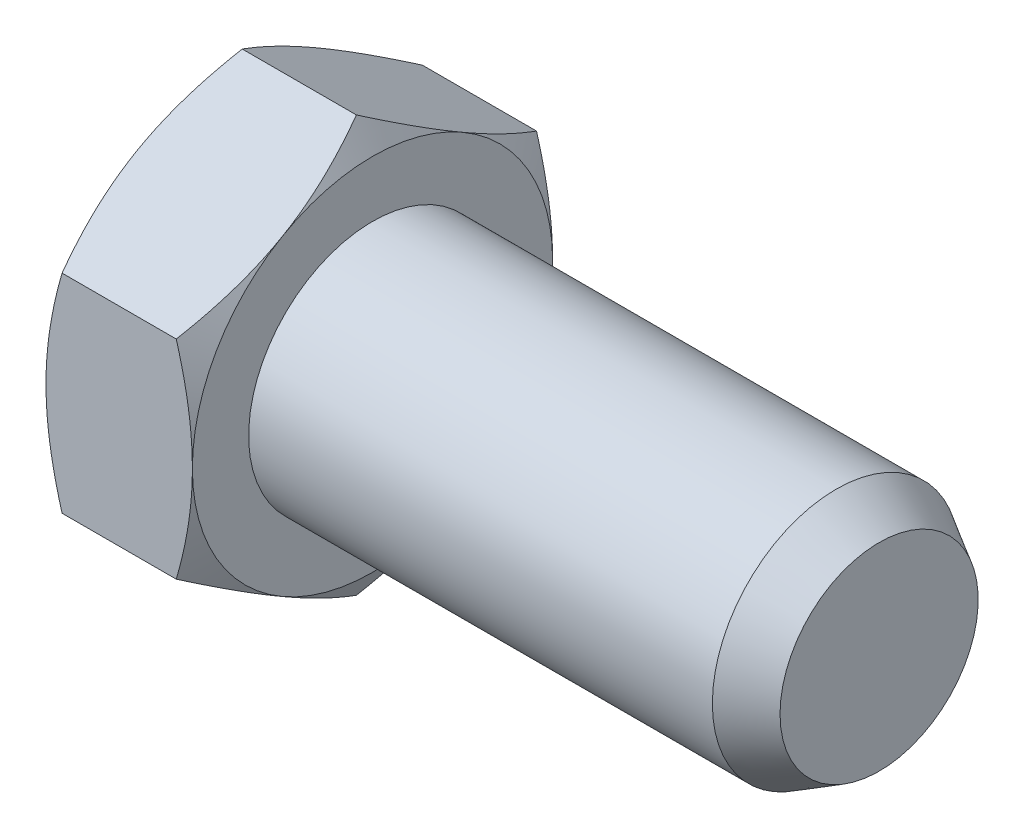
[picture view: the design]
ISO-10303-21;
HEADER;
FILE_DESCRIPTION(('STEP AP214'),'2;1');
FILE_NAME('part.step','',(''),(''),'','','');
FILE_SCHEMA(('AUTOMOTIVE_DESIGN { 1 0 10303 214 1 1 1 1 }'));
ENDSEC;
DATA;
#1=APPLICATION_CONTEXT('core data for automotive mechanical design processes');
#2=APPLICATION_PROTOCOL_DEFINITION('international standard','automotive_design',2000,#1);
#3=PRODUCT_CONTEXT('',#1,'mechanical');
#4=PRODUCT('Part','Part','',(#3));
#5=PRODUCT_RELATED_PRODUCT_CATEGORY('part','',(#4));
#6=PRODUCT_DEFINITION_FORMATION('','',#4);
#7=PRODUCT_DEFINITION_CONTEXT('part definition',#1,'design');
#8=PRODUCT_DEFINITION('design','',#6,#7);
#9=PRODUCT_DEFINITION_SHAPE('','',#8);
#10=(LENGTH_UNIT() NAMED_UNIT(*) SI_UNIT(.MILLI.,.METRE.));
#11=(NAMED_UNIT(*) PLANE_ANGLE_UNIT() SI_UNIT($,.RADIAN.));
#12=(NAMED_UNIT(*) SI_UNIT($,.STERADIAN.) SOLID_ANGLE_UNIT());
#13=UNCERTAINTY_MEASURE_WITH_UNIT(LENGTH_MEASURE(1.E-05),#10,'distance_accuracy_value','');
#14=(GEOMETRIC_REPRESENTATION_CONTEXT(3) GLOBAL_UNCERTAINTY_ASSIGNED_CONTEXT((#13)) GLOBAL_UNIT_ASSIGNED_CONTEXT((#10,
#11,#12)) REPRESENTATION_CONTEXT('',''));
#15=CARTESIAN_POINT('',(0.,0.,0.));
#16=DIRECTION('',(0.,0.,1.));
#17=DIRECTION('',(1.,0.,0.));
#18=AXIS2_PLACEMENT_3D('',#15,#16,#17);
#19=CARTESIAN_POINT('',(0.,0.,0.));
#20=DIRECTION('',(-1.,0.,0.));
#21=DIRECTION('',(0.,0.,1.));
#22=AXIS2_PLACEMENT_3D('',#19,#20,#21);
#23=PLANE('',#22);
#24=CARTESIAN_POINT('',(0.,0.,0.));
#25=DIRECTION('',(-1.,0.,0.));
#26=DIRECTION('',(0.,0.,1.));
#27=AXIS2_PLACEMENT_3D('',#24,#25,#26);
#28=CIRCLE('',#27,1.6);
#29=CARTESIAN_POINT('',(0.,0.,1.6));
#30=VERTEX_POINT('',#29);
#31=CARTESIAN_POINT('',(0.,-1.3856406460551,0.799999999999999));
#32=VERTEX_POINT('',#31);
#33=EDGE_CURVE('E167',#30,#32,#28,.F.);
#34=ORIENTED_EDGE('',*,*,#33,.F.);
#35=CARTESIAN_POINT('',(0.,1.3856406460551,0.8));
#36=VERTEX_POINT('',#35);
#37=EDGE_CURVE('E129',#36,#30,#28,.F.);
#38=ORIENTED_EDGE('',*,*,#37,.F.);
#39=CARTESIAN_POINT('',(0.,1.3856406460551,-0.799999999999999));
#40=VERTEX_POINT('',#39);
#41=EDGE_CURVE('E166',#40,#36,#28,.F.);
#42=ORIENTED_EDGE('',*,*,#41,.F.);
#43=CARTESIAN_POINT('',(0.,0.,-1.6));
#44=VERTEX_POINT('',#43);
#45=EDGE_CURVE('E298',#44,#40,#28,.F.);
#46=ORIENTED_EDGE('',*,*,#45,.F.);
#47=CARTESIAN_POINT('',(0.,-1.3856406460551,-0.8));
#48=VERTEX_POINT('',#47);
#49=EDGE_CURVE('E302',#48,#44,#28,.F.);
#50=ORIENTED_EDGE('',*,*,#49,.F.);
#51=EDGE_CURVE('E309',#32,#48,#28,.F.);
#52=ORIENTED_EDGE('',*,*,#51,.F.);
#53=EDGE_LOOP('',(#34,#38,#42,#46,#50,#52));
#54=FACE_BOUND('',#53,.T.);
#55=CARTESIAN_POINT('',(0.,0.,0.));
#56=DIRECTION('',(-1.,0.,0.));
#57=DIRECTION('',(0.,0.,1.));
#58=AXIS2_PLACEMENT_3D('',#55,#56,#57);
#59=CIRCLE('',#58,1.28);
#60=CARTESIAN_POINT('',(0.,0.,1.28));
#61=VERTEX_POINT('',#60);
#62=EDGE_CURVE('E176',#61,#61,#59,.F.);
#63=ORIENTED_EDGE('',*,*,#62,.T.);
#64=EDGE_LOOP('',(#63));
#65=FACE_BOUND('',#64,.T.);
#66=ADVANCED_FACE('F33',(#54,#65),#23,.T.);
#67=CARTESIAN_POINT('',(1.3,1.4,0.));
#68=DIRECTION('',(1.,0.,0.));
#69=DIRECTION('',(0.,0.,-1.));
#70=AXIS2_PLACEMENT_3D('',#67,#68,#69);
#71=PLANE('',#70);
#72=CARTESIAN_POINT('',(1.3,0.,0.));
#73=DIRECTION('',(1.,0.,0.));
#74=DIRECTION('',(0.,0.,-1.));
#75=AXIS2_PLACEMENT_3D('',#72,#73,#74);
#76=CIRCLE('',#75,1.6);
#77=CARTESIAN_POINT('',(1.3,-1.3856406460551,-0.8));
#78=VERTEX_POINT('',#77);
#79=CARTESIAN_POINT('',(1.3,0.,-1.6));
#80=VERTEX_POINT('',#79);
#81=EDGE_CURVE('E48',#78,#80,#76,.T.);
#82=ORIENTED_EDGE('',*,*,#81,.T.);
#83=CARTESIAN_POINT('',(1.3,1.3856406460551,-0.799999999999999));
#84=VERTEX_POINT('',#83);
#85=EDGE_CURVE('E56',#80,#84,#76,.T.);
#86=ORIENTED_EDGE('',*,*,#85,.T.);
#87=CARTESIAN_POINT('',(1.3,1.3856406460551,0.800000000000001));
#88=VERTEX_POINT('',#87);
#89=EDGE_CURVE('E345',#84,#88,#76,.T.);
#90=ORIENTED_EDGE('',*,*,#89,.T.);
#91=CARTESIAN_POINT('',(1.3,0.,1.6));
#92=VERTEX_POINT('',#91);
#93=EDGE_CURVE('E343',#88,#92,#76,.T.);
#94=ORIENTED_EDGE('',*,*,#93,.T.);
#95=CARTESIAN_POINT('',(1.3,-1.3856406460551,0.799999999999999));
#96=VERTEX_POINT('',#95);
#97=EDGE_CURVE('E339',#92,#96,#76,.T.);
#98=ORIENTED_EDGE('',*,*,#97,.T.);
#99=EDGE_CURVE('E332',#96,#78,#76,.T.);
#100=ORIENTED_EDGE('',*,*,#99,.T.);
#101=EDGE_LOOP('',(#82,#86,#90,#94,#98,#100));
#102=FACE_BOUND('',#101,.T.);
#103=CARTESIAN_POINT('',(1.3,0.,0.));
#104=DIRECTION('',(1.,0.,0.));
#105=DIRECTION('',(0.,0.,-1.));
#106=AXIS2_PLACEMENT_3D('',#103,#104,#105);
#107=CIRCLE('',#106,1.1);
#108=CARTESIAN_POINT('',(1.3,0.,-1.1));
#109=VERTEX_POINT('',#108);
#110=EDGE_CURVE('E161',#109,#109,#107,.T.);
#111=ORIENTED_EDGE('',*,*,#110,.F.);
#112=EDGE_LOOP('',(#111));
#113=FACE_BOUND('',#112,.T.);
#114=ADVANCED_FACE('F340',(#102,#113),#71,.T.);
#115=CARTESIAN_POINT('',(13.1078858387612,0.,0.));
#116=DIRECTION('',(1.,0.,0.));
#117=DIRECTION('',(0.,0.,-1.));
#118=AXIS2_PLACEMENT_3D('',#115,#116,#117);
#119=CYLINDRICAL_SURFACE('',#118,1.1);
#120=CARTESIAN_POINT('',(5.41894882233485,0.,0.));
#121=DIRECTION('',(1.,0.,0.));
#122=DIRECTION('',(0.,0.,-1.));
#123=AXIS2_PLACEMENT_3D('',#120,#121,#122);
#124=CIRCLE('',#123,1.1);
#125=CARTESIAN_POINT('',(5.41894882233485,0.,1.1));
#126=VERTEX_POINT('',#125);
#127=EDGE_CURVE('E11',#126,#126,#124,.F.);
#128=ORIENTED_EDGE('',*,*,#127,.T.);
#129=EDGE_LOOP('',(#128));
#130=FACE_BOUND('',#129,.T.);
#131=ORIENTED_EDGE('',*,*,#110,.T.);
#132=EDGE_LOOP('',(#131));
#133=FACE_BOUND('',#132,.T.);
#134=ADVANCED_FACE('F370',(#130,#133),#119,.T.);
#135=CARTESIAN_POINT('',(5.8,1.1,0.));
#136=DIRECTION('',(1.,0.,0.));
#137=DIRECTION('',(0.,0.,-1.));
#138=AXIS2_PLACEMENT_3D('',#135,#136,#137);
#139=PLANE('',#138);
#140=CARTESIAN_POINT('',(5.8,0.,0.));
#141=DIRECTION('',(1.,0.,0.));
#142=DIRECTION('',(0.,0.,-1.));
#143=AXIS2_PLACEMENT_3D('',#140,#141,#142);
#144=CIRCLE('',#143,0.879999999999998);
#145=CARTESIAN_POINT('',(5.8,0.,0.879999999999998));
#146=VERTEX_POINT('',#145);
#147=EDGE_CURVE('E41',#146,#146,#144,.T.);
#148=ORIENTED_EDGE('',*,*,#147,.T.);
#149=EDGE_LOOP('',(#148));
#150=FACE_BOUND('',#149,.T.);
#151=ADVANCED_FACE('F356',(#150),#139,.T.);
#152=CARTESIAN_POINT('',(0.65,0.,0.));
#153=DIRECTION('',(-1.,0.,0.));
#154=DIRECTION('',(0.,0.,1.));
#155=AXIS2_PLACEMENT_3D('',#152,#153,#154);
#156=CONICAL_SURFACE('',#155,2.72583302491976,1.04719755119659);
#157=CARTESIAN_POINT('',(1.15702709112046,-0.923644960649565,1.6002));
#158=CARTESIAN_POINT('',(1.18047613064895,-0.964240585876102,1.52988631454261));
#159=CARTESIAN_POINT('',(1.20180264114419,-1.00518662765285,1.45896568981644));
#160=CARTESIAN_POINT('',(1.23902934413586,-1.08778782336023,1.31589622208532));
#161=CARTESIAN_POINT('',(1.25491636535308,-1.12944444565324,1.24374483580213));
#162=CARTESIAN_POINT('',(1.27964828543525,-1.21224140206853,1.10033630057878));
#163=CARTESIAN_POINT('',(1.28865776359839,-1.25336899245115,1.02910122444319));
#164=CARTESIAN_POINT('',(1.299415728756,-1.33581782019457,0.886295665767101));
#165=CARTESIAN_POINT('',(1.30117312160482,-1.37713875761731,0.814725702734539));
#166=CARTESIAN_POINT('',(1.29752882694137,-1.45435771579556,0.680978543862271));
#167=CARTESIAN_POINT('',(1.29302194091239,-1.49026726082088,0.618781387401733));
#168=CARTESIAN_POINT('',(1.27873412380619,-1.5618523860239,0.494792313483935));
#169=CARTESIAN_POINT('',(1.26894830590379,-1.59752771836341,0.433000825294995));
#170=CARTESIAN_POINT('',(1.24448308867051,-1.66926059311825,0.30875584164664));
#171=CARTESIAN_POINT('',(1.22969992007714,-1.70530905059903,0.246318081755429));
#172=CARTESIAN_POINT('',(1.19614739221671,-1.77686812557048,0.122374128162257));
#173=CARTESIAN_POINT('',(1.17738592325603,-1.81237966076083,0.0608663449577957));
#174=CARTESIAN_POINT('',(1.15702709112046,-1.84763633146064,-0.000199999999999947));
#175=B_SPLINE_CURVE_WITH_KNOTS('',3,(#157,#158,#159,#160,#161,#162,#163,#164,#165,#166,#167,
#168,#169,#170,#171,#172,#173,#174),.UNSPECIFIED.,.F.,.F.,(4,2,2,2,2,2,2,2,4),(0.,
0.253628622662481,0.507867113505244,0.755812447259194,1.0034532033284,1.21912891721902,
1.43500463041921,1.65567058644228,1.87590291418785),.UNSPECIFIED.);
#176=CARTESIAN_POINT('',(1.15709376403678,-0.923760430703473,1.6));
#177=VERTEX_POINT('',#176);
#178=EDGE_CURVE('E157',#177,#96,#175,.T.);
#179=ORIENTED_EDGE('',*,*,#178,.T.);
#180=ORIENTED_EDGE('',*,*,#97,.F.);
#181=CARTESIAN_POINT('',(0.499873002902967,-2.52098464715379,1.6));
#182=CARTESIAN_POINT('',(0.534095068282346,-2.45076148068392,1.6));
#183=CARTESIAN_POINT('',(0.568000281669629,-2.38038131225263,1.6));
#184=CARTESIAN_POINT('',(0.634999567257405,-2.23922362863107,1.6));
#185=CARTESIAN_POINT('',(0.668093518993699,-2.16844605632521,1.6));
#186=CARTESIAN_POINT('',(0.733450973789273,-2.02606417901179,1.6));
#187=CARTESIAN_POINT('',(0.765709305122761,-1.95445749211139,1.6));
#188=CARTESIAN_POINT('',(0.828957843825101,-1.8106883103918,1.6));
#189=CARTESIAN_POINT('',(0.859948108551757,-1.73852584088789,1.6));
#190=CARTESIAN_POINT('',(0.921362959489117,-1.59104276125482,1.6));
#191=CARTESIAN_POINT('',(0.951731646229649,-1.51569874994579,1.6));
#192=CARTESIAN_POINT('',(1.01025914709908,-1.36415873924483,1.6));
#193=CARTESIAN_POINT('',(1.03841815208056,-1.28796281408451,1.6));
#194=CARTESIAN_POINT('',(1.09182525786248,-1.13470603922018,1.6));
#195=CARTESIAN_POINT('',(1.11707865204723,-1.05764705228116,1.6));
#196=CARTESIAN_POINT('',(1.16388736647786,-0.90242428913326,1.6));
#197=CARTESIAN_POINT('',(1.18544381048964,-0.824260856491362,1.6));
#198=CARTESIAN_POINT('',(1.22373292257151,-0.667228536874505,1.6));
#199=CARTESIAN_POINT('',(1.24049328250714,-0.588366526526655,1.6));
#200=CARTESIAN_POINT('',(1.26827361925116,-0.429622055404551,1.6));
#201=CARTESIAN_POINT('',(1.27929420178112,-0.349739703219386,1.6));
#202=CARTESIAN_POINT('',(1.2945707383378,-0.190409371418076,1.6));
#203=CARTESIAN_POINT('',(1.29891670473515,-0.110970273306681,1.6));
#204=CARTESIAN_POINT('',(1.30072544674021,0.0479847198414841,1.6));
#205=CARTESIAN_POINT('',(1.29818818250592,0.127500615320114,1.6));
#206=CARTESIAN_POINT('',(1.28423345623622,0.315948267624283,1.6));
#207=CARTESIAN_POINT('',(1.2698270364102,0.42466064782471,1.6));
#208=CARTESIAN_POINT('',(1.23056818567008,0.640184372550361,1.6));
#209=CARTESIAN_POINT('',(1.20570615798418,0.746993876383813,1.6));
#210=CARTESIAN_POINT('',(1.14763012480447,0.960879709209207,1.6));
#211=CARTESIAN_POINT('',(1.11423830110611,1.06790639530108,1.6));
#212=CARTESIAN_POINT('',(1.04181251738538,1.2799660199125,1.6));
#213=CARTESIAN_POINT('',(1.0027798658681,1.38499941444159,1.6));
#214=CARTESIAN_POINT('',(0.930792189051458,1.56799469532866,1.6));
#215=CARTESIAN_POINT('',(0.898685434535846,1.64629502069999,1.6));
#216=CARTESIAN_POINT('',(0.832721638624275,1.80215714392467,1.6));
#217=CARTESIAN_POINT('',(0.798864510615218,1.8797189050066,1.6));
#218=CARTESIAN_POINT('',(0.695256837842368,2.11154275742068,1.6));
#219=CARTESIAN_POINT('',(0.623487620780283,2.26490000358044,1.6));
#220=CARTESIAN_POINT('',(0.476501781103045,2.57016984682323,1.6));
#221=CARTESIAN_POINT('',(0.401280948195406,2.72208039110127,1.6));
#222=CARTESIAN_POINT('',(0.248594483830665,3.02477374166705,1.6));
#223=CARTESIAN_POINT('',(0.171128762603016,3.17555650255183,1.6));
#224=CARTESIAN_POINT('',(0.021984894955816,3.46221292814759,1.6));
#225=CARTESIAN_POINT('',(-0.0495548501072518,3.59815887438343,1.6));
#226=CARTESIAN_POINT('',(-0.1935806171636,3.86955633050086,1.6));
#227=CARTESIAN_POINT('',(-0.266066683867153,4.00500781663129,1.6));
#228=CARTESIAN_POINT('',(-0.411533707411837,4.27512524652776,1.6));
#229=CARTESIAN_POINT('',(-0.484512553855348,4.40979232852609,1.6));
#230=CARTESIAN_POINT('',(-0.631022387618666,4.67881425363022,1.6));
#231=CARTESIAN_POINT('',(-0.704553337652,4.81316911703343,1.6));
#232=CARTESIAN_POINT('',(-0.778287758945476,4.94741144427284,1.6));
#233=B_SPLINE_CURVE_WITH_KNOTS('',3,(#181,#182,#183,#184,#185,#186,#187,#188,#189,#190,#191,
#192,#193,#194,#195,#196,#197,#198,#199,#200,#201,#202,#203,#204,#205,#206,#207,#208,#209,#210,
#211,#212,#213,#214,#215,#216,#217,#218,#219,#220,#221,#222,#223,#224,#225,#226,#227,#228,#229,
#230,#231,#232),.UNSPECIFIED.,.F.,.F.,(4,2,2,2,2,2,2,2,2,2,2,2,2,2,2,2,2,2,2,2,2,2,2,2,2,4),(0.,
0.234357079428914,0.468748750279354,0.704350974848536,0.939942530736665,1.18361811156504,
1.42727262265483,1.67047597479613,1.91360526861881,2.15530105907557,2.39697133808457,
2.63535296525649,2.87373597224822,3.20204898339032,3.53066399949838,3.86678588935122,
4.2028299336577,4.45668877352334,4.71056018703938,5.21844347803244,5.72696367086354,
6.23550422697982,6.69636122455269,7.15724007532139,7.61674952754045,8.0762282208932),.UNSPECIFIED.);
#234=EDGE_CURVE('E168',#92,#177,#233,.F.);
#235=ORIENTED_EDGE('',*,*,#234,.T.);
#236=EDGE_LOOP('',(#179,#180,#235));
#237=FACE_BOUND('',#236,.T.);
#238=ADVANCED_FACE('F376',(#237),#156,.T.);
#239=CARTESIAN_POINT('',(1.15702709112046,1.84763633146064,-0.0001999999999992));
#240=CARTESIAN_POINT('',(1.18047613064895,1.8070407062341,0.0701136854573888));
#241=CARTESIAN_POINT('',(1.20180264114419,1.76609466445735,0.14103431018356));
#242=CARTESIAN_POINT('',(1.23902934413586,1.68349346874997,0.284103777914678));
#243=CARTESIAN_POINT('',(1.25491636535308,1.64183684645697,0.356255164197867));
#244=CARTESIAN_POINT('',(1.27964828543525,1.55903989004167,0.499663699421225));
#245=CARTESIAN_POINT('',(1.28865776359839,1.51791229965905,0.570898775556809));
#246=CARTESIAN_POINT('',(1.299415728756,1.43546347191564,0.713704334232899));
#247=CARTESIAN_POINT('',(1.30117312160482,1.39414253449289,0.785274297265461));
#248=CARTESIAN_POINT('',(1.29752882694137,1.31692357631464,0.919021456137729));
#249=CARTESIAN_POINT('',(1.29302194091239,1.28101403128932,0.981218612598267));
#250=CARTESIAN_POINT('',(1.27873412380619,1.20942890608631,1.10520768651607));
#251=CARTESIAN_POINT('',(1.26894830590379,1.1737535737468,1.16699917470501));
#252=CARTESIAN_POINT('',(1.24448308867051,1.10202069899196,1.29124415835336));
#253=CARTESIAN_POINT('',(1.22969992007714,1.06597224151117,1.35368191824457));
#254=CARTESIAN_POINT('',(1.19614739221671,0.994413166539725,1.47762587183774));
#255=CARTESIAN_POINT('',(1.17738592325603,0.958901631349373,1.5391336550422));
#256=CARTESIAN_POINT('',(1.15702709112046,0.923644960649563,1.6002));
#257=B_SPLINE_CURVE_WITH_KNOTS('',3,(#239,#240,#241,#242,#243,#244,#245,#246,#247,#248,#249,
#250,#251,#252,#253,#254,#255,#256),.UNSPECIFIED.,.F.,.F.,(4,2,2,2,2,2,2,2,4),(0.,
0.253628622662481,0.507867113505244,0.755812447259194,1.0034532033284,1.21912891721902,
1.43500463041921,1.65567058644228,1.87590291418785),.UNSPECIFIED.);
#258=CARTESIAN_POINT('',(1.15709376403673,0.923760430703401,1.6));
#259=VERTEX_POINT('',#258);
#260=EDGE_CURVE('E317',#88,#259,#257,.T.);
#261=ORIENTED_EDGE('',*,*,#260,.T.);
#262=EDGE_CURVE('E150',#259,#92,#233,.F.);
#263=ORIENTED_EDGE('',*,*,#262,.T.);
#264=ORIENTED_EDGE('',*,*,#93,.F.);
#265=EDGE_LOOP('',(#261,#263,#264));
#266=FACE_BOUND('',#265,.T.);
#267=ADVANCED_FACE('F177',(#266),#156,.T.);
#268=CARTESIAN_POINT('',(1.15702709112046,0.923644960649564,-1.6002));
#269=CARTESIAN_POINT('',(1.18047613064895,0.964240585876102,-1.52988631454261));
#270=CARTESIAN_POINT('',(1.20180264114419,1.00518662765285,-1.45896568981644));
#271=CARTESIAN_POINT('',(1.23902934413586,1.08778782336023,-1.31589622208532));
#272=CARTESIAN_POINT('',(1.25491636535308,1.12944444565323,-1.24374483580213));
#273=CARTESIAN_POINT('',(1.27964828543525,1.21224140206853,-1.10033630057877));
#274=CARTESIAN_POINT('',(1.28865776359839,1.25336899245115,-1.02910122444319));
#275=CARTESIAN_POINT('',(1.299415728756,1.33581782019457,-0.886295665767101));
#276=CARTESIAN_POINT('',(1.30117312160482,1.37713875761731,-0.814725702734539));
#277=CARTESIAN_POINT('',(1.29752882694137,1.45435771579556,-0.680978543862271));
#278=CARTESIAN_POINT('',(1.29302194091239,1.49026726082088,-0.618781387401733));
#279=CARTESIAN_POINT('',(1.27873412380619,1.5618523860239,-0.494792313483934));
#280=CARTESIAN_POINT('',(1.26894830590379,1.59752771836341,-0.433000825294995));
#281=CARTESIAN_POINT('',(1.24448308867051,1.66926059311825,-0.30875584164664));
#282=CARTESIAN_POINT('',(1.22969992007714,1.70530905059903,-0.246318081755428));
#283=CARTESIAN_POINT('',(1.19614739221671,1.77686812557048,-0.122374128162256));
#284=CARTESIAN_POINT('',(1.17738592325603,1.81237966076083,-0.0608663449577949));
#285=CARTESIAN_POINT('',(1.15702709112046,1.84763633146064,0.000200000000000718));
#286=B_SPLINE_CURVE_WITH_KNOTS('',3,(#268,#269,#270,#271,#272,#273,#274,#275,#276,#277,#278,
#279,#280,#281,#282,#283,#284,#285),.UNSPECIFIED.,.F.,.F.,(4,2,2,2,2,2,2,2,4),(0.,
0.253628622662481,0.507867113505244,0.755812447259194,1.0034532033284,1.21912891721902,
1.43500463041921,1.65567058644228,1.87590291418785),.UNSPECIFIED.);
#287=CARTESIAN_POINT('',(1.15709376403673,1.8475208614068,0.));
#288=VERTEX_POINT('',#287);
#289=EDGE_CURVE('E261',#84,#288,#286,.T.);
#290=ORIENTED_EDGE('',*,*,#289,.T.);
#291=EDGE_CURVE('E321',#288,#88,#257,.T.);
#292=ORIENTED_EDGE('',*,*,#291,.T.);
#293=ORIENTED_EDGE('',*,*,#89,.F.);
#294=EDGE_LOOP('',(#290,#292,#293));
#295=FACE_BOUND('',#294,.T.);
#296=ADVANCED_FACE('F351',(#295),#156,.T.);
#297=CARTESIAN_POINT('',(0.499873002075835,-2.5209846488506,-1.6));
#298=CARTESIAN_POINT('',(0.53409506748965,-2.45076148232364,-1.6));
#299=CARTESIAN_POINT('',(0.568000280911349,-2.38038131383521,-1.6));
#300=CARTESIAN_POINT('',(0.634999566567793,-2.23922363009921,-1.6));
#301=CARTESIAN_POINT('',(0.668093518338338,-2.16844605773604,-1.6));
#302=CARTESIAN_POINT('',(0.733450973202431,-2.02606418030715,-1.6));
#303=CARTESIAN_POINT('',(0.765709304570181,-1.95445749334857,-1.6));
#304=CARTESIAN_POINT('',(0.828957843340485,-1.81068831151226,-1.6));
#305=CARTESIAN_POINT('',(0.859948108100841,-1.73852584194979,-1.6));
#306=CARTESIAN_POINT('',(0.921362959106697,-1.59104276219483,-1.6));
#307=CARTESIAN_POINT('',(0.951731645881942,-1.51569875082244,-1.6));
#308=CARTESIAN_POINT('',(1.01025914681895,-1.36415873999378,-1.6));
#309=CARTESIAN_POINT('',(1.0384181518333,-1.28796281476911,-1.6));
#310=CARTESIAN_POINT('',(1.09182525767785,-1.1347060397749,-1.6));
#311=CARTESIAN_POINT('',(1.11707865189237,-1.05764705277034,-1.6));
#312=CARTESIAN_POINT('',(1.16388736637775,-0.902424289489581,-1.6));
#313=CARTESIAN_POINT('',(1.1854438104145,-0.824260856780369,-1.6));
#314=CARTESIAN_POINT('',(1.22373292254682,-0.667228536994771,-1.6));
#315=CARTESIAN_POINT('',(1.24049328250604,-0.588366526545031,-1.6));
#316=CARTESIAN_POINT('',(1.26827361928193,-0.429622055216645,-1.6));
#317=CARTESIAN_POINT('',(1.27929420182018,-0.349739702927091,-1.6));
#318=CARTESIAN_POINT('',(1.29457073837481,-0.190409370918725,-1.6));
#319=CARTESIAN_POINT('',(1.29891670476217,-0.110970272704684,-1.6));
#320=CARTESIAN_POINT('',(1.30072544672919,0.0479847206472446,-1.6));
#321=CARTESIAN_POINT('',(1.29818818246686,0.127500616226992,-1.6));
#322=CARTESIAN_POINT('',(1.28423345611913,0.315948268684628,-1.6));
#323=CARTESIAN_POINT('',(1.26982703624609,0.424660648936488,-1.6));
#324=CARTESIAN_POINT('',(1.23056818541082,0.640184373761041,-1.6));
#325=CARTESIAN_POINT('',(1.20570615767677,0.746993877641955,-1.6));
#326=CARTESIAN_POINT('',(1.14763012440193,0.960879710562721,-1.6));
#327=CARTESIAN_POINT('',(1.11423830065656,1.06790639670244,-1.6));
#328=CARTESIAN_POINT('',(1.0418125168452,1.27996602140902,-1.6));
#329=CARTESIAN_POINT('',(1.0027798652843,1.38499941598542,-1.6));
#330=CARTESIAN_POINT('',(0.930792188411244,1.56799469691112,-1.6));
#331=CARTESIAN_POINT('',(0.898685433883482,1.64629502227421,-1.6));
#332=CARTESIAN_POINT('',(0.832721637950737,1.80215714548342,-1.6));
#333=CARTESIAN_POINT('',(0.798864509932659,1.87971890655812,-1.6));
#334=CARTESIAN_POINT('',(0.695256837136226,2.11154275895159,-1.6));
#335=CARTESIAN_POINT('',(0.623487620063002,2.26490000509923,-1.6));
#336=CARTESIAN_POINT('',(0.476501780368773,2.57016984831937,-1.6));
#337=CARTESIAN_POINT('',(0.401280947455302,2.7220803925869,-1.6));
#338=CARTESIAN_POINT('',(0.248594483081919,3.02477374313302,-1.6));
#339=CARTESIAN_POINT('',(0.171128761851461,3.17555650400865,-1.6));
#340=CARTESIAN_POINT('',(0.0219848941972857,3.46221292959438,-1.6));
#341=CARTESIAN_POINT('',(-0.0495548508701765,3.59815887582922,-1.6));
#342=CARTESIAN_POINT('',(-0.193580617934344,3.86955633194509,-1.6));
#343=CARTESIAN_POINT('',(-0.266066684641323,4.00500781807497,-1.6));
#344=CARTESIAN_POINT('',(-0.411533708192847,4.2751252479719,-1.6));
#345=CARTESIAN_POINT('',(-0.48451255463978,4.40979232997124,-1.6));
#346=CARTESIAN_POINT('',(-0.631022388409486,4.67881425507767,-1.6));
#347=CARTESIAN_POINT('',(-0.704553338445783,4.81316911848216,-1.6));
#348=CARTESIAN_POINT('',(-0.778287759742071,4.94741144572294,-1.6));
#349=B_SPLINE_CURVE_WITH_KNOTS('',3,(#297,#298,#299,#300,#301,#302,#303,#304,#305,#306,#307,
#308,#309,#310,#311,#312,#313,#314,#315,#316,#317,#318,#319,#320,#321,#322,#323,#324,#325,#326,
#327,#328,#329,#330,#331,#332,#333,#334,#335,#336,#337,#338,#339,#340,#341,#342,#343,#344,#345,
#346,#347,#348),.UNSPECIFIED.,.F.,.F.,(4,2,2,2,2,2,2,2,2,2,2,2,2,2,2,2,2,2,2,2,2,2,2,2,2,4),(0.,
0.234357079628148,0.468748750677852,0.704350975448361,0.939942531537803,1.1836181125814,
1.42727262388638,1.67047597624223,1.9136052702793,2.1553010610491,2.3969713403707,
2.63535296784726,2.87373597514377,3.20204898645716,3.53066400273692,3.86678589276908,
4.20282993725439,4.45668877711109,4.71056019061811,5.21844348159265,5.7269636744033,
6.23550423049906,6.69636122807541,7.15724007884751,7.61674953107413,8.07622822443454),.UNSPECIFIED.);
#350=CARTESIAN_POINT('',(1.15709376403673,0.923760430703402,-1.6));
#351=VERTEX_POINT('',#350);
#352=EDGE_CURVE('E252',#80,#351,#349,.T.);
#353=ORIENTED_EDGE('',*,*,#352,.T.);
#354=EDGE_CURVE('E260',#351,#84,#286,.T.);
#355=ORIENTED_EDGE('',*,*,#354,.T.);
#356=ORIENTED_EDGE('',*,*,#85,.F.);
#357=EDGE_LOOP('',(#353,#355,#356));
#358=FACE_BOUND('',#357,.T.);
#359=ADVANCED_FACE('F388',(#358),#156,.T.);
#360=CARTESIAN_POINT('',(1.15702709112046,-1.84763633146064,0.0002));
#361=CARTESIAN_POINT('',(1.18047613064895,-1.8070407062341,-0.0701136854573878));
#362=CARTESIAN_POINT('',(1.20180264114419,-1.76609466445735,-0.141034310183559));
#363=CARTESIAN_POINT('',(1.23902934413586,-1.68349346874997,-0.284103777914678));
#364=CARTESIAN_POINT('',(1.25491636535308,-1.64183684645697,-0.356255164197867));
#365=CARTESIAN_POINT('',(1.27964828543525,-1.55903989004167,-0.499663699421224));
#366=CARTESIAN_POINT('',(1.28865776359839,-1.51791229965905,-0.570898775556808));
#367=CARTESIAN_POINT('',(1.299415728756,-1.43546347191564,-0.713704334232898));
#368=CARTESIAN_POINT('',(1.30117312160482,-1.39414253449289,-0.78527429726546));
#369=CARTESIAN_POINT('',(1.29752882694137,-1.31692357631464,-0.919021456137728));
#370=CARTESIAN_POINT('',(1.29302194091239,-1.28101403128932,-0.981218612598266));
#371=CARTESIAN_POINT('',(1.27873412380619,-1.20942890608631,-1.10520768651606));
#372=CARTESIAN_POINT('',(1.26894830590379,-1.1737535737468,-1.166999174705));
#373=CARTESIAN_POINT('',(1.24448308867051,-1.10202069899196,-1.29124415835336));
#374=CARTESIAN_POINT('',(1.22969992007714,-1.06597224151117,-1.35368191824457));
#375=CARTESIAN_POINT('',(1.19614739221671,-0.994413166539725,-1.47762587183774));
#376=CARTESIAN_POINT('',(1.17738592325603,-0.958901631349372,-1.5391336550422));
#377=CARTESIAN_POINT('',(1.15702709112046,-0.923644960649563,-1.6002));
#378=B_SPLINE_CURVE_WITH_KNOTS('',3,(#360,#361,#362,#363,#364,#365,#366,#367,#368,#369,#370,
#371,#372,#373,#374,#375,#376,#377),.UNSPECIFIED.,.F.,.F.,(4,2,2,2,2,2,2,2,4),(0.,
0.253628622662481,0.507867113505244,0.755812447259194,1.0034532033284,1.21912891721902,
1.43500463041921,1.65567058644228,1.87590291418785),.UNSPECIFIED.);
#379=CARTESIAN_POINT('',(1.15709376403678,-0.923760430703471,-1.6));
#380=VERTEX_POINT('',#379);
#381=EDGE_CURVE('E266',#78,#380,#378,.T.);
#382=ORIENTED_EDGE('',*,*,#381,.T.);
#383=EDGE_CURVE('E259',#380,#80,#349,.T.);
#384=ORIENTED_EDGE('',*,*,#383,.T.);
#385=ORIENTED_EDGE('',*,*,#81,.F.);
#386=EDGE_LOOP('',(#382,#384,#385));
#387=FACE_BOUND('',#386,.T.);
#388=ADVANCED_FACE('F384',(#387),#156,.T.);
#389=CARTESIAN_POINT('',(1.15709376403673,-1.8475208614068,0.));
#390=VERTEX_POINT('',#389);
#391=EDGE_CURVE('E273',#96,#390,#175,.T.);
#392=ORIENTED_EDGE('',*,*,#391,.T.);
#393=EDGE_CURVE('E272',#390,#78,#378,.T.);
#394=ORIENTED_EDGE('',*,*,#393,.T.);
#395=ORIENTED_EDGE('',*,*,#99,.F.);
#396=EDGE_LOOP('',(#392,#394,#395));
#397=FACE_BOUND('',#396,.T.);
#398=ADVANCED_FACE('F185',(#397),#156,.T.);
#399=CARTESIAN_POINT('',(1.3,-0.923760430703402,1.6));
#400=DIRECTION('',(0.,0.,1.));
#401=DIRECTION('',(0.,-1.,0.));
#402=AXIS2_PLACEMENT_3D('',#399,#400,#401);
#403=PLANE('',#402);
#404=ORIENTED_EDGE('',*,*,#262,.F.);
#405=DIRECTION('',(-1.,0.,0.));
#406=VECTOR('',#405,1.);
#407=CARTESIAN_POINT('',(1.3,0.923760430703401,1.6));
#408=LINE('',#407,#406);
#409=CARTESIAN_POINT('',(0.142906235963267,0.923760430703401,1.6));
#410=VERTEX_POINT('',#409);
#411=EDGE_CURVE('E142',#259,#410,#408,.T.);
#412=ORIENTED_EDGE('',*,*,#411,.T.);
#413=CARTESIAN_POINT('',(0.800126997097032,-2.52098464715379,1.6));
#414=CARTESIAN_POINT('',(0.765904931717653,-2.45076148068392,1.6));
#415=CARTESIAN_POINT('',(0.73199971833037,-2.38038131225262,1.6));
#416=CARTESIAN_POINT('',(0.665000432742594,-2.23922362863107,1.6));
#417=CARTESIAN_POINT('',(0.6319064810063,-2.16844605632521,1.6));
#418=CARTESIAN_POINT('',(0.566549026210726,-2.02606417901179,1.6));
#419=CARTESIAN_POINT('',(0.534290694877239,-1.95445749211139,1.6));
#420=CARTESIAN_POINT('',(0.471042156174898,-1.8106883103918,1.6));
#421=CARTESIAN_POINT('',(0.440051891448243,-1.73852584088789,1.6));
#422=CARTESIAN_POINT('',(0.378637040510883,-1.59104276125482,1.6));
#423=CARTESIAN_POINT('',(0.348268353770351,-1.51569874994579,1.6));
#424=CARTESIAN_POINT('',(0.289740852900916,-1.36415873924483,1.6));
#425=CARTESIAN_POINT('',(0.261581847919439,-1.28796281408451,1.6));
#426=CARTESIAN_POINT('',(0.208174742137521,-1.13470603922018,1.6));
#427=CARTESIAN_POINT('',(0.182921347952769,-1.05764705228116,1.6));
#428=CARTESIAN_POINT('',(0.136112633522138,-0.90242428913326,1.6));
#429=CARTESIAN_POINT('',(0.114556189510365,-0.824260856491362,1.6));
#430=CARTESIAN_POINT('',(0.0762670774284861,-0.667228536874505,1.6));
#431=CARTESIAN_POINT('',(0.0595067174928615,-0.588366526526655,1.6));
#432=CARTESIAN_POINT('',(0.0317263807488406,-0.42962205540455,1.6));
#433=CARTESIAN_POINT('',(0.0207057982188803,-0.349739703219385,1.6));
#434=CARTESIAN_POINT('',(0.00542926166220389,-0.190409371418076,1.6));
#435=CARTESIAN_POINT('',(0.00108329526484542,-0.11097027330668,1.6));
#436=CARTESIAN_POINT('',(-0.000725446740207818,0.0479847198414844,1.6));
#437=CARTESIAN_POINT('',(0.00181181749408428,0.127500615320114,1.6));
#438=CARTESIAN_POINT('',(0.0157665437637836,0.315948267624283,1.6));
#439=CARTESIAN_POINT('',(0.0301729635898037,0.42466064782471,1.6));
#440=CARTESIAN_POINT('',(0.0694318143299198,0.640184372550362,1.6));
#441=CARTESIAN_POINT('',(0.0942938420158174,0.746993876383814,1.6));
#442=CARTESIAN_POINT('',(0.152369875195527,0.960879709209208,1.6));
#443=CARTESIAN_POINT('',(0.185761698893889,1.06790639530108,1.6));
#444=CARTESIAN_POINT('',(0.258187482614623,1.2799660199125,1.6));
#445=CARTESIAN_POINT('',(0.297220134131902,1.38499941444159,1.6));
#446=CARTESIAN_POINT('',(0.369207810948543,1.56799469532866,1.6));
#447=CARTESIAN_POINT('',(0.401314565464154,1.64629502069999,1.6));
#448=CARTESIAN_POINT('',(0.467278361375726,1.80215714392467,1.6));
#449=CARTESIAN_POINT('',(0.501135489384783,1.8797189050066,1.6));
#450=CARTESIAN_POINT('',(0.604743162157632,2.11154275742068,1.6));
#451=CARTESIAN_POINT('',(0.676512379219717,2.26490000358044,1.6));
#452=CARTESIAN_POINT('',(0.823498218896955,2.57016984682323,1.6));
#453=CARTESIAN_POINT('',(0.898719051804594,2.72208039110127,1.6));
#454=CARTESIAN_POINT('',(1.05140551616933,3.02477374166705,1.6));
#455=CARTESIAN_POINT('',(1.12887123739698,3.17555650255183,1.6));
#456=CARTESIAN_POINT('',(1.27801510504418,3.4622129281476,1.6));
#457=CARTESIAN_POINT('',(1.34955485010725,3.59815887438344,1.6));
#458=CARTESIAN_POINT('',(1.4935806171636,3.86955633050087,1.6));
#459=CARTESIAN_POINT('',(1.56606668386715,4.0050078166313,1.6));
#460=CARTESIAN_POINT('',(1.71153370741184,4.27512524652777,1.6));
#461=CARTESIAN_POINT('',(1.78451255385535,4.40979232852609,1.6));
#462=CARTESIAN_POINT('',(1.93102238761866,4.67881425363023,1.6));
#463=CARTESIAN_POINT('',(2.004553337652,4.81316911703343,1.6));
#464=CARTESIAN_POINT('',(2.07828775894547,4.94741144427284,1.6));
#465=B_SPLINE_CURVE_WITH_KNOTS('',3,(#413,#414,#415,#416,#417,#418,#419,#420,#421,#422,#423,
#424,#425,#426,#427,#428,#429,#430,#431,#432,#433,#434,#435,#436,#437,#438,#439,#440,#441,#442,
#443,#444,#445,#446,#447,#448,#449,#450,#451,#452,#453,#454,#455,#456,#457,#458,#459,#460,#461,
#462,#463,#464),.UNSPECIFIED.,.F.,.F.,(4,2,2,2,2,2,2,2,2,2,2,2,2,2,2,2,2,2,2,2,2,2,2,2,2,4),(0.,
0.234357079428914,0.468748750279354,0.704350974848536,0.939942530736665,1.18361811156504,
1.42727262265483,1.67047597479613,1.91360526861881,2.15530105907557,2.39697133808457,
2.63535296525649,2.87373597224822,3.20204898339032,3.53066399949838,3.86678588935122,
4.2028299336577,4.45668877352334,4.71056018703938,5.21844347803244,5.72696367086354,
6.23550422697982,6.69636122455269,7.15724007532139,7.61674952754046,8.0762282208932),.UNSPECIFIED.);
#466=EDGE_CURVE('E124',#30,#410,#465,.T.);
#467=ORIENTED_EDGE('',*,*,#466,.F.);
#468=CARTESIAN_POINT('',(0.142906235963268,-0.923760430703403,1.6));
#469=VERTEX_POINT('',#468);
#470=EDGE_CURVE('E135',#469,#30,#465,.T.);
#471=ORIENTED_EDGE('',*,*,#470,.F.);
#472=DIRECTION('',(-1.,0.,0.));
#473=VECTOR('',#472,1.);
#474=CARTESIAN_POINT('',(1.3,-0.923760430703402,1.6));
#475=LINE('',#474,#473);
#476=EDGE_CURVE('E152',#177,#469,#475,.T.);
#477=ORIENTED_EDGE('',*,*,#476,.F.);
#478=ORIENTED_EDGE('',*,*,#234,.F.);
#479=EDGE_LOOP('',(#404,#412,#467,#471,#477,#478));
#480=FACE_BOUND('',#479,.T.);
#481=ADVANCED_FACE('F148',(#480),#403,.T.);
#482=CARTESIAN_POINT('',(1.3,0.923760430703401,1.6));
#483=DIRECTION('',(0.,0.866025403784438,0.5));
#484=DIRECTION('',(0.,-0.5,0.866025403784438));
#485=AXIS2_PLACEMENT_3D('',#482,#483,#484);
#486=PLANE('',#485);
#487=ORIENTED_EDGE('',*,*,#291,.F.);
#488=DIRECTION('',(-1.,0.,0.));
#489=VECTOR('',#488,1.);
#490=CARTESIAN_POINT('',(1.3,1.8475208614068,0.));
#491=LINE('',#490,#489);
#492=CARTESIAN_POINT('',(0.142906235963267,1.8475208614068,0.));
#493=VERTEX_POINT('',#492);
#494=EDGE_CURVE('E151',#288,#493,#491,.T.);
#495=ORIENTED_EDGE('',*,*,#494,.T.);
#496=CARTESIAN_POINT('',(0.142972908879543,0.923644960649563,1.6002));
#497=CARTESIAN_POINT('',(0.119523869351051,0.964240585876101,1.52988631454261));
#498=CARTESIAN_POINT('',(0.0981973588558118,1.00518662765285,1.45896568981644));
#499=CARTESIAN_POINT('',(0.0609706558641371,1.08778782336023,1.31589622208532));
#500=CARTESIAN_POINT('',(0.0450836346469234,1.12944444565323,1.24374483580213));
#501=CARTESIAN_POINT('',(0.0203517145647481,1.21224140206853,1.10033630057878));
#502=CARTESIAN_POINT('',(0.0113422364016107,1.25336899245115,1.02910122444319));
#503=CARTESIAN_POINT('',(0.000584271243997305,1.33581782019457,0.886295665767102));
#504=CARTESIAN_POINT('',(-0.00117312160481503,1.37713875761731,0.81472570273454));
#505=CARTESIAN_POINT('',(0.00247117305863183,1.45435771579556,0.680978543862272));
#506=CARTESIAN_POINT('',(0.00697805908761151,1.49026726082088,0.618781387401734));
#507=CARTESIAN_POINT('',(0.0212658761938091,1.56185238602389,0.494792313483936));
#508=CARTESIAN_POINT('',(0.0310516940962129,1.59752771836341,0.433000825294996));
#509=CARTESIAN_POINT('',(0.0555169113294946,1.66926059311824,0.308755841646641));
#510=CARTESIAN_POINT('',(0.0703000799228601,1.70530905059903,0.24631808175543));
#511=CARTESIAN_POINT('',(0.103852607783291,1.77686812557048,0.122374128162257));
#512=CARTESIAN_POINT('',(0.122614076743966,1.81237966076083,0.0608663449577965));
#513=CARTESIAN_POINT('',(0.142972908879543,1.84763633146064,-0.000199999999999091));
#514=B_SPLINE_CURVE_WITH_KNOTS('',3,(#496,#497,#498,#499,#500,#501,#502,#503,#504,#505,#506,
#507,#508,#509,#510,#511,#512,#513),.UNSPECIFIED.,.F.,.F.,(4,2,2,2,2,2,2,2,4),(0.,
0.253628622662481,0.507867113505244,0.755812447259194,1.0034532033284,1.21912891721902,
1.43500463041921,1.65567058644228,1.87590291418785),.UNSPECIFIED.);
#515=EDGE_CURVE('E144',#36,#493,#514,.T.);
#516=ORIENTED_EDGE('',*,*,#515,.F.);
#517=EDGE_CURVE('E127',#410,#36,#514,.T.);
#518=ORIENTED_EDGE('',*,*,#517,.F.);
#519=ORIENTED_EDGE('',*,*,#411,.F.);
#520=ORIENTED_EDGE('',*,*,#260,.F.);
#521=EDGE_LOOP('',(#487,#495,#516,#518,#519,#520));
#522=FACE_BOUND('',#521,.T.);
#523=ADVANCED_FACE('F140',(#522),#486,.T.);
#524=CARTESIAN_POINT('',(1.3,1.8475208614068,0.));
#525=DIRECTION('',(0.,0.866025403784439,-0.5));
#526=DIRECTION('',(0.,0.5,0.866025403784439));
#527=AXIS2_PLACEMENT_3D('',#524,#525,#526);
#528=PLANE('',#527);
#529=ORIENTED_EDGE('',*,*,#354,.F.);
#530=DIRECTION('',(-1.,0.,0.));
#531=VECTOR('',#530,1.);
#532=CARTESIAN_POINT('',(1.3,0.923760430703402,-1.6));
#533=LINE('',#532,#531);
#534=CARTESIAN_POINT('',(0.142906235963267,0.923760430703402,-1.6));
#535=VERTEX_POINT('',#534);
#536=EDGE_CURVE('E154',#351,#535,#533,.T.);
#537=ORIENTED_EDGE('',*,*,#536,.T.);
#538=CARTESIAN_POINT('',(0.142972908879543,1.84763633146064,0.000200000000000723));
#539=CARTESIAN_POINT('',(0.119523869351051,1.8070407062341,-0.0701136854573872));
#540=CARTESIAN_POINT('',(0.0981973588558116,1.76609466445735,-0.141034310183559));
#541=CARTESIAN_POINT('',(0.0609706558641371,1.68349346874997,-0.284103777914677));
#542=CARTESIAN_POINT('',(0.0450836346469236,1.64183684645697,-0.356255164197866));
#543=CARTESIAN_POINT('',(0.0203517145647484,1.55903989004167,-0.499663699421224));
#544=CARTESIAN_POINT('',(0.0113422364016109,1.51791229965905,-0.570898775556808));
#545=CARTESIAN_POINT('',(0.000584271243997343,1.43546347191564,-0.713704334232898));
#546=CARTESIAN_POINT('',(-0.001173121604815,1.3941425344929,-0.78527429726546));
#547=CARTESIAN_POINT('',(0.00247117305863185,1.31692357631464,-0.919021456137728));
#548=CARTESIAN_POINT('',(0.00697805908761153,1.28101403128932,-0.981218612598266));
#549=CARTESIAN_POINT('',(0.0212658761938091,1.20942890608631,-1.10520768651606));
#550=CARTESIAN_POINT('',(0.0310516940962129,1.1737535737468,-1.166999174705));
#551=CARTESIAN_POINT('',(0.0555169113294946,1.10202069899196,-1.29124415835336));
#552=CARTESIAN_POINT('',(0.0703000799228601,1.06597224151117,-1.35368191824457));
#553=CARTESIAN_POINT('',(0.103852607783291,0.994413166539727,-1.47762587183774));
#554=CARTESIAN_POINT('',(0.122614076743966,0.958901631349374,-1.5391336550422));
#555=CARTESIAN_POINT('',(0.142972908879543,0.923644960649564,-1.6002));
#556=B_SPLINE_CURVE_WITH_KNOTS('',3,(#538,#539,#540,#541,#542,#543,#544,#545,#546,#547,#548,
#549,#550,#551,#552,#553,#554,#555),.UNSPECIFIED.,.F.,.F.,(4,2,2,2,2,2,2,2,4),(0.,
0.253628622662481,0.507867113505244,0.755812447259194,1.0034532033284,1.21912891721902,
1.43500463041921,1.65567058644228,1.87590291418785),.UNSPECIFIED.);
#557=EDGE_CURVE('E235',#40,#535,#556,.T.);
#558=ORIENTED_EDGE('',*,*,#557,.F.);
#559=EDGE_CURVE('E222',#493,#40,#556,.T.);
#560=ORIENTED_EDGE('',*,*,#559,.F.);
#561=ORIENTED_EDGE('',*,*,#494,.F.);
#562=ORIENTED_EDGE('',*,*,#289,.F.);
#563=EDGE_LOOP('',(#529,#537,#558,#560,#561,#562));
#564=FACE_BOUND('',#563,.T.);
#565=ADVANCED_FACE('F246',(#564),#528,.T.);
#566=CARTESIAN_POINT('',(1.3,0.923760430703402,-1.6));
#567=DIRECTION('',(0.,0.,-1.));
#568=DIRECTION('',(0.,1.,0.));
#569=AXIS2_PLACEMENT_3D('',#566,#567,#568);
#570=PLANE('',#569);
#571=ORIENTED_EDGE('',*,*,#383,.F.);
#572=DIRECTION('',(-1.,0.,0.));
#573=VECTOR('',#572,1.);
#574=CARTESIAN_POINT('',(1.3,-0.9237604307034,-1.6));
#575=LINE('',#574,#573);
#576=CARTESIAN_POINT('',(0.14290623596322,-0.923760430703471,-1.6));
#577=VERTEX_POINT('',#576);
#578=EDGE_CURVE('E281',#380,#577,#575,.T.);
#579=ORIENTED_EDGE('',*,*,#578,.T.);
#580=CARTESIAN_POINT('',(0.800126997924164,-2.5209846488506,-1.6));
#581=CARTESIAN_POINT('',(0.76590493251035,-2.45076148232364,-1.6));
#582=CARTESIAN_POINT('',(0.73199971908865,-2.38038131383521,-1.6));
#583=CARTESIAN_POINT('',(0.665000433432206,-2.23922363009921,-1.6));
#584=CARTESIAN_POINT('',(0.631906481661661,-2.16844605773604,-1.6));
#585=CARTESIAN_POINT('',(0.566549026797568,-2.02606418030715,-1.6));
#586=CARTESIAN_POINT('',(0.534290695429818,-1.95445749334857,-1.6));
#587=CARTESIAN_POINT('',(0.471042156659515,-1.81068831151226,-1.6));
#588=CARTESIAN_POINT('',(0.440051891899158,-1.73852584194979,-1.6));
#589=CARTESIAN_POINT('',(0.378637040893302,-1.59104276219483,-1.6));
#590=CARTESIAN_POINT('',(0.348268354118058,-1.51569875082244,-1.6));
#591=CARTESIAN_POINT('',(0.289740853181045,-1.36415873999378,-1.6));
#592=CARTESIAN_POINT('',(0.261581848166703,-1.28796281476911,-1.6));
#593=CARTESIAN_POINT('',(0.208174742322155,-1.1347060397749,-1.6));
#594=CARTESIAN_POINT('',(0.182921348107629,-1.05764705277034,-1.6));
#595=CARTESIAN_POINT('',(0.136112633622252,-0.902424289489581,-1.6));
#596=CARTESIAN_POINT('',(0.114556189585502,-0.824260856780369,-1.6));
#597=CARTESIAN_POINT('',(0.0762670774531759,-0.667228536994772,-1.6));
#598=CARTESIAN_POINT('',(0.0595067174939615,-0.588366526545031,-1.6));
#599=CARTESIAN_POINT('',(0.0317263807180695,-0.429622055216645,-1.6));
#600=CARTESIAN_POINT('',(0.0207057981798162,-0.349739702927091,-1.6));
#601=CARTESIAN_POINT('',(0.00542926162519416,-0.190409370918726,-1.6));
#602=CARTESIAN_POINT('',(0.00108329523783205,-0.110970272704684,-1.6));
#603=CARTESIAN_POINT('',(-0.000725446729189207,0.0479847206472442,-1.6));
#604=CARTESIAN_POINT('',(0.00181181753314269,0.127500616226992,-1.6));
#605=CARTESIAN_POINT('',(0.0157665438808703,0.315948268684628,-1.6));
#606=CARTESIAN_POINT('',(0.0301729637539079,0.424660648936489,-1.6));
#607=CARTESIAN_POINT('',(0.0694318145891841,0.640184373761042,-1.6));
#608=CARTESIAN_POINT('',(0.0942938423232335,0.746993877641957,-1.6));
#609=CARTESIAN_POINT('',(0.152369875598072,0.960879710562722,-1.6));
#610=CARTESIAN_POINT('',(0.185761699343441,1.06790639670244,-1.6));
#611=CARTESIAN_POINT('',(0.258187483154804,1.27996602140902,-1.6));
#612=CARTESIAN_POINT('',(0.297220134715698,1.38499941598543,-1.6));
#613=CARTESIAN_POINT('',(0.369207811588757,1.56799469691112,-1.6));
#614=CARTESIAN_POINT('',(0.401314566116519,1.64629502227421,-1.6));
#615=CARTESIAN_POINT('',(0.467278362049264,1.80215714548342,-1.6));
#616=CARTESIAN_POINT('',(0.501135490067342,1.87971890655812,-1.6));
#617=CARTESIAN_POINT('',(0.604743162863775,2.11154275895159,-1.6));
#618=CARTESIAN_POINT('',(0.676512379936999,2.26490000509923,-1.6));
#619=CARTESIAN_POINT('',(0.823498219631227,2.57016984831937,-1.6));
#620=CARTESIAN_POINT('',(0.898719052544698,2.7220803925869,-1.6));
#621=CARTESIAN_POINT('',(1.05140551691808,3.02477374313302,-1.6));
#622=CARTESIAN_POINT('',(1.12887123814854,3.17555650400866,-1.6));
#623=CARTESIAN_POINT('',(1.27801510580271,3.46221292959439,-1.6));
#624=CARTESIAN_POINT('',(1.34955485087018,3.59815887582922,-1.6));
#625=CARTESIAN_POINT('',(1.49358061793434,3.86955633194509,-1.6));
#626=CARTESIAN_POINT('',(1.56606668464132,4.00500781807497,-1.6));
#627=CARTESIAN_POINT('',(1.71153370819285,4.27512524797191,-1.6));
#628=CARTESIAN_POINT('',(1.78451255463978,4.40979232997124,-1.6));
#629=CARTESIAN_POINT('',(1.93102238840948,4.67881425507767,-1.6));
#630=CARTESIAN_POINT('',(2.00455333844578,4.81316911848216,-1.6));
#631=CARTESIAN_POINT('',(2.07828775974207,4.94741144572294,-1.6));
#632=B_SPLINE_CURVE_WITH_KNOTS('',3,(#580,#581,#582,#583,#584,#585,#586,#587,#588,#589,#590,
#591,#592,#593,#594,#595,#596,#597,#598,#599,#600,#601,#602,#603,#604,#605,#606,#607,#608,#609,
#610,#611,#612,#613,#614,#615,#616,#617,#618,#619,#620,#621,#622,#623,#624,#625,#626,#627,#628,
#629,#630,#631),.UNSPECIFIED.,.F.,.F.,(4,2,2,2,2,2,2,2,2,2,2,2,2,2,2,2,2,2,2,2,2,2,2,2,2,4),(0.,
0.234357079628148,0.468748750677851,0.70435097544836,0.939942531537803,1.1836181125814,
1.42727262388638,1.67047597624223,1.9136052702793,2.1553010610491,2.3969713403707,
2.63535296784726,2.87373597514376,3.20204898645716,3.53066400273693,3.86678589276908,
4.20282993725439,4.45668877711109,4.71056019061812,5.21844348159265,5.7269636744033,
6.23550423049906,6.69636122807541,7.15724007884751,7.61674953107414,8.07622822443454),.UNSPECIFIED.);
#633=EDGE_CURVE('E234',#44,#577,#632,.F.);
#634=ORIENTED_EDGE('',*,*,#633,.F.);
#635=EDGE_CURVE('E228',#535,#44,#632,.F.);
#636=ORIENTED_EDGE('',*,*,#635,.F.);
#637=ORIENTED_EDGE('',*,*,#536,.F.);
#638=ORIENTED_EDGE('',*,*,#352,.F.);
#639=EDGE_LOOP('',(#571,#579,#634,#636,#637,#638));
#640=FACE_BOUND('',#639,.T.);
#641=ADVANCED_FACE('F242',(#640),#570,.T.);
#642=CARTESIAN_POINT('',(1.3,-0.9237604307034,-1.6));
#643=DIRECTION('',(0.,-0.866025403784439,-0.5));
#644=DIRECTION('',(0.,0.5,-0.866025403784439));
#645=AXIS2_PLACEMENT_3D('',#642,#643,#644);
#646=PLANE('',#645);
#647=ORIENTED_EDGE('',*,*,#393,.F.);
#648=DIRECTION('',(-1.,0.,0.));
#649=VECTOR('',#648,1.);
#650=CARTESIAN_POINT('',(1.3,-1.8475208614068,0.));
#651=LINE('',#650,#649);
#652=CARTESIAN_POINT('',(0.142906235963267,-1.8475208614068,0.));
#653=VERTEX_POINT('',#652);
#654=EDGE_CURVE('E164',#390,#653,#651,.T.);
#655=ORIENTED_EDGE('',*,*,#654,.T.);
#656=CARTESIAN_POINT('',(0.142972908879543,-0.923644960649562,-1.6002));
#657=CARTESIAN_POINT('',(0.119523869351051,-0.9642405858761,-1.52988631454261));
#658=CARTESIAN_POINT('',(0.0981973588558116,-1.00518662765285,-1.45896568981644));
#659=CARTESIAN_POINT('',(0.0609706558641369,-1.08778782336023,-1.31589622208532));
#660=CARTESIAN_POINT('',(0.0450836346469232,-1.12944444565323,-1.24374483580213));
#661=CARTESIAN_POINT('',(0.0203517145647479,-1.21224140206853,-1.10033630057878));
#662=CARTESIAN_POINT('',(0.0113422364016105,-1.25336899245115,-1.02910122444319));
#663=CARTESIAN_POINT('',(0.000584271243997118,-1.33581782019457,-0.886295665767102));
#664=CARTESIAN_POINT('',(-0.00117312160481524,-1.37713875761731,-0.81472570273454));
#665=CARTESIAN_POINT('',(0.00247117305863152,-1.45435771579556,-0.680978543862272));
#666=CARTESIAN_POINT('',(0.00697805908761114,-1.49026726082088,-0.618781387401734));
#667=CARTESIAN_POINT('',(0.0212658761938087,-1.56185238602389,-0.494792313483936));
#668=CARTESIAN_POINT('',(0.0310516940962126,-1.59752771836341,-0.433000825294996));
#669=CARTESIAN_POINT('',(0.0555169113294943,-1.66926059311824,-0.308755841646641));
#670=CARTESIAN_POINT('',(0.0703000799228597,-1.70530905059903,-0.246318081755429));
#671=CARTESIAN_POINT('',(0.103852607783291,-1.77686812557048,-0.122374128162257));
#672=CARTESIAN_POINT('',(0.122614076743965,-1.81237966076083,-0.0608663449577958));
#673=CARTESIAN_POINT('',(0.142972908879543,-1.84763633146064,0.000199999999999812));
#674=B_SPLINE_CURVE_WITH_KNOTS('',3,(#656,#657,#658,#659,#660,#661,#662,#663,#664,#665,#666,
#667,#668,#669,#670,#671,#672,#673),.UNSPECIFIED.,.F.,.F.,(4,2,2,2,2,2,2,2,4),(0.,
0.253628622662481,0.507867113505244,0.755812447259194,1.0034532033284,1.21912891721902,
1.43500463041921,1.65567058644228,1.87590291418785),.UNSPECIFIED.);
#675=EDGE_CURVE('E318',#48,#653,#674,.T.);
#676=ORIENTED_EDGE('',*,*,#675,.F.);
#677=EDGE_CURVE('E236',#577,#48,#674,.T.);
#678=ORIENTED_EDGE('',*,*,#677,.F.);
#679=ORIENTED_EDGE('',*,*,#578,.F.);
#680=ORIENTED_EDGE('',*,*,#381,.F.);
#681=EDGE_LOOP('',(#647,#655,#676,#678,#679,#680));
#682=FACE_BOUND('',#681,.T.);
#683=ADVANCED_FACE('F245',(#682),#646,.T.);
#684=CARTESIAN_POINT('',(1.3,-1.8475208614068,0.));
#685=DIRECTION('',(0.,-0.866025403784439,0.499999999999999));
#686=DIRECTION('',(0.,-0.499999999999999,-0.866025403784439));
#687=AXIS2_PLACEMENT_3D('',#684,#685,#686);
#688=PLANE('',#687);
#689=ORIENTED_EDGE('',*,*,#178,.F.);
#690=ORIENTED_EDGE('',*,*,#476,.T.);
#691=CARTESIAN_POINT('',(0.142972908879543,-1.84763633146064,-0.000199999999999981));
#692=CARTESIAN_POINT('',(0.119523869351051,-1.8070407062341,0.070113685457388));
#693=CARTESIAN_POINT('',(0.0981973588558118,-1.76609466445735,0.141034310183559));
#694=CARTESIAN_POINT('',(0.0609706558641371,-1.68349346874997,0.284103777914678));
#695=CARTESIAN_POINT('',(0.0450836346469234,-1.64183684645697,0.356255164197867));
#696=CARTESIAN_POINT('',(0.0203517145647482,-1.55903989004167,0.499663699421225));
#697=CARTESIAN_POINT('',(0.0113422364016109,-1.51791229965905,0.570898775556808));
#698=CARTESIAN_POINT('',(0.000584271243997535,-1.43546347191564,0.713704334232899));
#699=CARTESIAN_POINT('',(-0.00117312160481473,-1.3941425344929,0.78527429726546));
#700=CARTESIAN_POINT('',(0.00247117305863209,-1.31692357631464,0.919021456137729));
#701=CARTESIAN_POINT('',(0.00697805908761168,-1.28101403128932,0.981218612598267));
#702=CARTESIAN_POINT('',(0.0212658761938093,-1.20942890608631,1.10520768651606));
#703=CARTESIAN_POINT('',(0.0310516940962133,-1.1737535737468,1.166999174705));
#704=CARTESIAN_POINT('',(0.0555169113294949,-1.10202069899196,1.29124415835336));
#705=CARTESIAN_POINT('',(0.0703000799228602,-1.06597224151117,1.35368191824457));
#706=CARTESIAN_POINT('',(0.103852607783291,-0.994413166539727,1.47762587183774));
#707=CARTESIAN_POINT('',(0.122614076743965,-0.958901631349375,1.5391336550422));
#708=CARTESIAN_POINT('',(0.142972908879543,-0.923644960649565,1.6002));
#709=B_SPLINE_CURVE_WITH_KNOTS('',3,(#691,#692,#693,#694,#695,#696,#697,#698,#699,#700,#701,
#702,#703,#704,#705,#706,#707,#708),.UNSPECIFIED.,.F.,.F.,(4,2,2,2,2,2,2,2,4),(0.,
0.253628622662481,0.507867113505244,0.755812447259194,1.0034532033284,1.21912891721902,
1.43500463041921,1.65567058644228,1.87590291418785),.UNSPECIFIED.);
#710=EDGE_CURVE('E145',#32,#469,#709,.T.);
#711=ORIENTED_EDGE('',*,*,#710,.F.);
#712=EDGE_CURVE('E315',#653,#32,#709,.T.);
#713=ORIENTED_EDGE('',*,*,#712,.F.);
#714=ORIENTED_EDGE('',*,*,#654,.F.);
#715=ORIENTED_EDGE('',*,*,#391,.F.);
#716=EDGE_LOOP('',(#689,#690,#711,#713,#714,#715));
#717=FACE_BOUND('',#716,.T.);
#718=ADVANCED_FACE('F188',(#717),#688,.T.);
#719=CARTESIAN_POINT('',(-0.923760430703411,0.,0.));
#720=DIRECTION('',(1.,0.,0.));
#721=DIRECTION('',(0.,0.,-1.));
#722=AXIS2_PLACEMENT_3D('',#719,#720,#721);
#723=CONICAL_SURFACE('',#722,0.,1.04719755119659);
#724=ORIENTED_EDGE('',*,*,#517,.T.);
#725=ORIENTED_EDGE('',*,*,#37,.T.);
#726=ORIENTED_EDGE('',*,*,#466,.T.);
#727=EDGE_LOOP('',(#724,#725,#726));
#728=FACE_BOUND('',#727,.T.);
#729=ADVANCED_FACE('F126',(#728),#723,.T.);
#730=ORIENTED_EDGE('',*,*,#559,.T.);
#731=ORIENTED_EDGE('',*,*,#41,.T.);
#732=ORIENTED_EDGE('',*,*,#515,.T.);
#733=EDGE_LOOP('',(#730,#731,#732));
#734=FACE_BOUND('',#733,.T.);
#735=ADVANCED_FACE('F206',(#734),#723,.T.);
#736=ORIENTED_EDGE('',*,*,#635,.T.);
#737=ORIENTED_EDGE('',*,*,#45,.T.);
#738=ORIENTED_EDGE('',*,*,#557,.T.);
#739=EDGE_LOOP('',(#736,#737,#738));
#740=FACE_BOUND('',#739,.T.);
#741=ADVANCED_FACE('F296',(#740),#723,.T.);
#742=ORIENTED_EDGE('',*,*,#677,.T.);
#743=ORIENTED_EDGE('',*,*,#49,.T.);
#744=ORIENTED_EDGE('',*,*,#633,.T.);
#745=EDGE_LOOP('',(#742,#743,#744));
#746=FACE_BOUND('',#745,.T.);
#747=ADVANCED_FACE('F303',(#746),#723,.T.);
#748=ORIENTED_EDGE('',*,*,#712,.T.);
#749=ORIENTED_EDGE('',*,*,#51,.T.);
#750=ORIENTED_EDGE('',*,*,#675,.T.);
#751=EDGE_LOOP('',(#748,#749,#750));
#752=FACE_BOUND('',#751,.T.);
#753=ADVANCED_FACE('F207',(#752),#723,.T.);
#754=ORIENTED_EDGE('',*,*,#470,.T.);
#755=ORIENTED_EDGE('',*,*,#33,.T.);
#756=ORIENTED_EDGE('',*,*,#710,.T.);
#757=EDGE_LOOP('',(#754,#755,#756));
#758=FACE_BOUND('',#757,.T.);
#759=ADVANCED_FACE('F208',(#758),#723,.T.);
#760=CARTESIAN_POINT('',(0.,0.,0.));
#761=DIRECTION('',(-1.,0.,0.));
#762=DIRECTION('',(0.,-1.,0.));
#763=AXIS2_PLACEMENT_3D('',#760,#761,#762);
#764=CYLINDRICAL_SURFACE('',#763,1.28);
#765=ORIENTED_EDGE('',*,*,#62,.F.);
#766=EDGE_LOOP('',(#765));
#767=FACE_BOUND('',#766,.T.);
#768=CARTESIAN_POINT('',(0.4,0.,0.));
#769=DIRECTION('',(-1.,0.,0.));
#770=DIRECTION('',(0.,-1.,0.));
#771=AXIS2_PLACEMENT_3D('',#768,#769,#770);
#772=CIRCLE('',#771,1.28);
#773=CARTESIAN_POINT('',(0.4,-1.28,0.));
#774=VERTEX_POINT('',#773);
#775=EDGE_CURVE('E347',#774,#774,#772,.T.);
#776=ORIENTED_EDGE('',*,*,#775,.F.);
#777=EDGE_LOOP('',(#776));
#778=FACE_BOUND('',#777,.T.);
#779=ADVANCED_FACE('F209',(#767,#778),#764,.F.);
#780=CARTESIAN_POINT('',(0.4,1.28,0.));
#781=DIRECTION('',(-1.,0.,0.));
#782=DIRECTION('',(0.,-1.,0.));
#783=AXIS2_PLACEMENT_3D('',#780,#781,#782);
#784=PLANE('',#783);
#785=ORIENTED_EDGE('',*,*,#775,.T.);
#786=EDGE_LOOP('',(#785));
#787=FACE_BOUND('',#786,.T.);
#788=ADVANCED_FACE('F359',(#787),#784,.T.);
#789=CARTESIAN_POINT('',(5.8,0.,0.));
#790=DIRECTION('',(-1.,0.,0.));
#791=DIRECTION('',(0.,0.,1.));
#792=AXIS2_PLACEMENT_3D('',#789,#790,#791);
#793=CONICAL_SURFACE('',#792,0.879999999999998,0.5235987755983);
#794=CARTESIAN_POINT('',(5.41894882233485,0.,1.1));
#795=CARTESIAN_POINT('',(5.42291810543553,0.,1.09770833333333));
#796=CARTESIAN_POINT('',(5.4268873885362,0.,1.09541666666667));
#797=CARTESIAN_POINT('',(5.43482595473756,0.,1.09083333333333));
#798=CARTESIAN_POINT('',(5.43879523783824,0.,1.08854166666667));
#799=CARTESIAN_POINT('',(5.4467338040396,0.,1.08395833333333));
#800=CARTESIAN_POINT('',(5.45070308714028,0.,1.08166666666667));
#801=CARTESIAN_POINT('',(5.45864165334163,0.,1.07708333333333));
#802=CARTESIAN_POINT('',(5.46261093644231,0.,1.07479166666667));
#803=CARTESIAN_POINT('',(5.47054950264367,0.,1.07020833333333));
#804=CARTESIAN_POINT('',(5.47451878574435,0.,1.06791666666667));
#805=CARTESIAN_POINT('',(5.4824573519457,0.,1.06333333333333));
#806=CARTESIAN_POINT('',(5.48642663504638,0.,1.06104166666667));
#807=CARTESIAN_POINT('',(5.49436520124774,0.,1.05645833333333));
#808=CARTESIAN_POINT('',(5.49833448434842,0.,1.05416666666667));
#809=CARTESIAN_POINT('',(5.50627305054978,0.,1.04958333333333));
#810=CARTESIAN_POINT('',(5.51024233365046,0.,1.04729166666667));
#811=CARTESIAN_POINT('',(5.51818089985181,0.,1.04270833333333));
#812=CARTESIAN_POINT('',(5.52215018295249,0.,1.04041666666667));
#813=CARTESIAN_POINT('',(5.53008874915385,0.,1.03583333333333));
#814=CARTESIAN_POINT('',(5.53405803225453,0.,1.03354166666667));
#815=CARTESIAN_POINT('',(5.54199659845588,0.,1.02895833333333));
#816=CARTESIAN_POINT('',(5.54596588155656,0.,1.02666666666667));
#817=CARTESIAN_POINT('',(5.55390444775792,0.,1.02208333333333));
#818=CARTESIAN_POINT('',(5.5578737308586,0.,1.01979166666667));
#819=CARTESIAN_POINT('',(5.56581229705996,0.,1.01520833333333));
#820=CARTESIAN_POINT('',(5.56978158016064,0.,1.01291666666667));
#821=CARTESIAN_POINT('',(5.57772014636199,0.,1.00833333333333));
#822=CARTESIAN_POINT('',(5.58168942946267,0.,1.00604166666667));
#823=CARTESIAN_POINT('',(5.58962799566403,0.,1.00145833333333));
#824=CARTESIAN_POINT('',(5.59359727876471,0.,0.999166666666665));
#825=CARTESIAN_POINT('',(5.60153584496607,0.,0.994583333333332));
#826=CARTESIAN_POINT('',(5.60550512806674,0.,0.992291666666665));
#827=CARTESIAN_POINT('',(5.6134436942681,0.,0.987708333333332));
#828=CARTESIAN_POINT('',(5.61741297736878,0.,0.985416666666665));
#829=CARTESIAN_POINT('',(5.62535154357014,0.,0.980833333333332));
#830=CARTESIAN_POINT('',(5.62932082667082,0.,0.978541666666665));
#831=CARTESIAN_POINT('',(5.63725939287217,0.,0.973958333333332));
#832=CARTESIAN_POINT('',(5.64122867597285,0.,0.971666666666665));
#833=CARTESIAN_POINT('',(5.64916724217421,0.,0.967083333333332));
#834=CARTESIAN_POINT('',(5.65313652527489,0.,0.964791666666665));
#835=CARTESIAN_POINT('',(5.66107509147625,0.,0.960208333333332));
#836=CARTESIAN_POINT('',(5.66504437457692,0.,0.957916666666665));
#837=CARTESIAN_POINT('',(5.67298294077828,0.,0.953333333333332));
#838=CARTESIAN_POINT('',(5.67695222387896,0.,0.951041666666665));
#839=CARTESIAN_POINT('',(5.68489079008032,0.,0.946458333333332));
#840=CARTESIAN_POINT('',(5.688860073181,0.,0.944166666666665));
#841=CARTESIAN_POINT('',(5.69679863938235,0.,0.939583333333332));
#842=CARTESIAN_POINT('',(5.70076792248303,0.,0.937291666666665));
#843=CARTESIAN_POINT('',(5.70870648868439,0.,0.932708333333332));
#844=CARTESIAN_POINT('',(5.71267577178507,0.,0.930416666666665));
#845=CARTESIAN_POINT('',(5.72061433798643,0.,0.925833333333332));
#846=CARTESIAN_POINT('',(5.7245836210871,0.,0.923541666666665));
#847=CARTESIAN_POINT('',(5.73252218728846,0.,0.918958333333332));
#848=CARTESIAN_POINT('',(5.73649147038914,0.,0.916666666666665));
#849=CARTESIAN_POINT('',(5.7444300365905,0.,0.912083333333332));
#850=CARTESIAN_POINT('',(5.74839931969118,0.,0.909791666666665));
#851=CARTESIAN_POINT('',(5.75633788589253,0.,0.905208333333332));
#852=CARTESIAN_POINT('',(5.76030716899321,0.,0.902916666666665));
#853=CARTESIAN_POINT('',(5.76824573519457,0.,0.898333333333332));
#854=CARTESIAN_POINT('',(5.77221501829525,0.,0.896041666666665));
#855=CARTESIAN_POINT('',(5.78015358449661,0.,0.891458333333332));
#856=CARTESIAN_POINT('',(5.78412286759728,0.,0.889166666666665));
#857=CARTESIAN_POINT('',(5.79206143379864,0.,0.884583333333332));
#858=CARTESIAN_POINT('',(5.79603071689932,0.,0.882291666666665));
#859=CARTESIAN_POINT('',(5.8,0.,0.879999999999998));
#860=B_SPLINE_CURVE_WITH_KNOTS('',3,(#794,#795,#796,#797,#798,#799,#800,#801,#802,#803,#804,
#805,#806,#807,#808,#809,#810,#811,#812,#813,#814,#815,#816,#817,#818,#819,#820,#821,#822,#823,
#824,#825,#826,#827,#828,#829,#830,#831,#832,#833,#834,#835,#836,#837,#838,#839,#840,#841,#842,
#843,#844,#845,#846,#847,#848,#849,#850,#851,#852,#853,#854,#855,#856,#857,#858,#859),
.UNSPECIFIED.,.F.,.F.,(4,2,2,2,2,2,2,2,2,2,2,2,2,2,2,2,2,2,2,2,2,2,2,2,2,2,2,2,2,2,2,2,4),(0.,
0.01375,0.0274999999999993,0.0412499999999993,0.0549999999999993,0.0687499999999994,
0.0824999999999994,0.0962499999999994,0.109999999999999,0.123749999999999,0.1375,0.15125,0.165,
0.17875,0.1925,0.20625,0.22,0.23375,0.2475,0.26125,0.275,0.28875,0.3025,0.31625,0.33,0.34375,
0.3575,0.37125,0.385,0.39875,0.4125,0.42625,0.44),.UNSPECIFIED.);
#861=EDGE_CURVE('BSEAM35',#126,#146,#860,.T.);
#862=ORIENTED_EDGE('',*,*,#127,.F.);
#863=ORIENTED_EDGE('',*,*,#147,.F.);
#864=ORIENTED_EDGE('',*,*,#861,.T.);
#865=ORIENTED_EDGE('',*,*,#861,.F.);
#866=EDGE_LOOP('',(#862,#864,#863,#865));
#867=FACE_BOUND('',#866,.T.);
#868=ADVANCED_FACE('F35',(#867),#793,.T.);
#869=CLOSED_SHELL('',(#66,#114,#134,#151,#238,#267,#296,#359,#388,#398,#481,#523,#565,#641,#683,
#718,#729,#735,#741,#747,#753,#759,#779,#788,#868));
#870=MANIFOLD_SOLID_BREP('B2',#869);
#871=ADVANCED_BREP_SHAPE_REPRESENTATION('',(#18,#870),#14);
#872=SHAPE_DEFINITION_REPRESENTATION(#9,#871);
ENDSEC;
END-ISO-10303-21;
